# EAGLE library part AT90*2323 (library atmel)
MICROCONTROLLER 2 Kbytes FLASH 128 bytes SRAM 128 bytes EEPROM

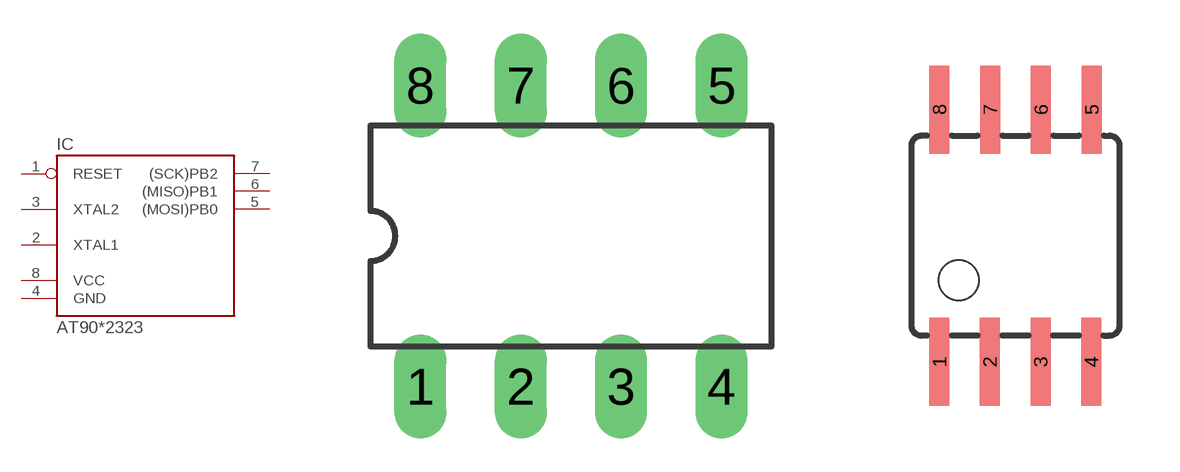
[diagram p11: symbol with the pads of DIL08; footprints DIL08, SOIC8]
Designator prefix IC

## AT90LS2323P (OC_FARNELL: unknown; OC_NEWARK: unknown), AT90S2323P (OC_FARNELL: unknown; OC_NEWARK: unknown)  [DIL08]
1  RESET  in
2  XTAL1
3  XTAL2
4  GND  pwr
5  (MOSI)PB0
6  (MISO)PB1
7  (SCK)PB2
8  VCC  pwr

## AT90LS2323S (OC_FARNELL: unknown; OC_NEWARK: unknown), AT90S2323S (OC_FARNELL: unknown; OC_NEWARK: unknown)  [SOIC8]
Pads as for DIL08

## Footprint DIL08 (pad centres in mm)
Dual In Line
drill 0.813 long: 1 -3.81,-3.81; 2 -1.27,-3.81; 3 1.27,-3.81; 4 3.81,-3.81; 5 3.81,3.81; 6 1.27,3.81; 7 -1.27,3.81; 8 -3.81,3.81

## Footprint SOIC8 (pad centres in mm)
Wide Plastic Gull Wing Small Outline Package
smd 0.5 x 2.2: 1 -1.905,-3.154; 2 -0.645,-3.154; 3 0.625,-3.154; 4 1.895,-3.154; 5 1.905,3.154; 6 0.635,3.154; 7 -0.635,3.154; 8 -1.905,3.154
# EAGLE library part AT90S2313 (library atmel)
MICROCONTROLLER 2 Kbytes FLASH 128 bytes SRAM 128 bytes EEPROM UART

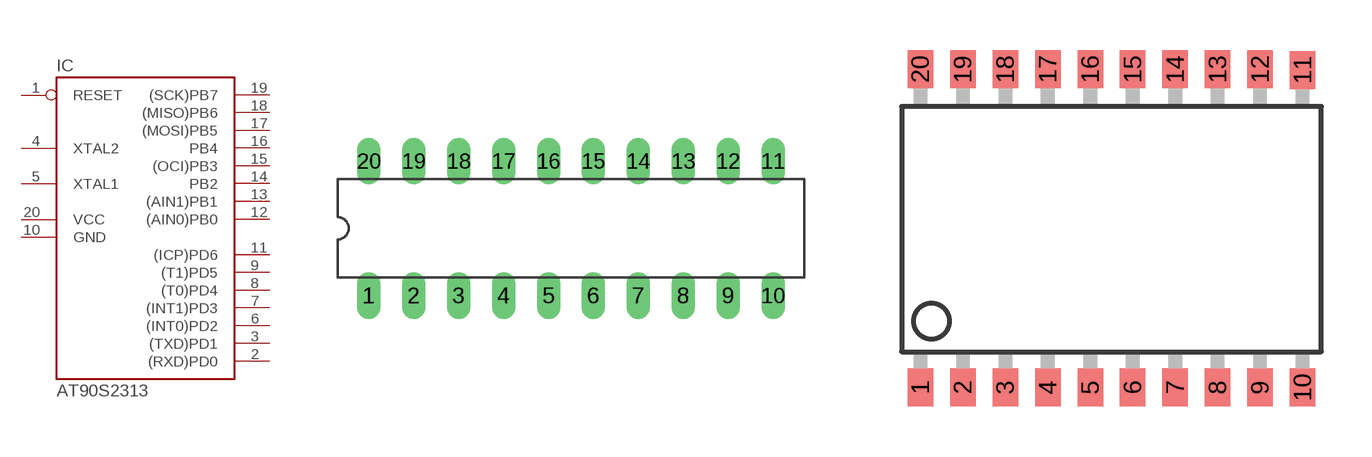
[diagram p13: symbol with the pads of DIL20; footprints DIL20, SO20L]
Designator prefix IC

## AT90S2313P (OC_FARNELL: unknown; OC_NEWARK: unknown)  [DIL20]
1  RESET
2  (RXD)PD0
3  (TXD)PD1
4  XTAL2
5  XTAL1
6  (INT0)PD2
7  (INT1)PD3
8  (T0)PD4
9  (T1)PD5
10  GND  pwr
11  (ICP)PD6
12  (AIN0)PB0
13  (AIN1)PB1
14  PB2
15  (OCI)PB3
16  PB4
17  (MOSI)PB5
18  (MISO)PB6
19  (SCK)PB7
20  VCC  pwr

## AT90S2313S (OC_FARNELL: unknown; OC_NEWARK: unknown)  [SO20L]
Pads as for DIL20

## Footprint DIL20 (pad centres in mm)
Dual In Line
drill 0.813 long: 1 -11.43,-3.81; 2 -8.89,-3.81; 3 -6.35,-3.81; 4 -3.81,-3.81; 5 -1.27,-3.81; 6 1.27,-3.81; 7 3.81,-3.81; 8 6.35,-3.81; 9 8.89,-3.81; 10 11.43,-3.81; 11 11.43,3.81; 12 8.89,3.81; 13 6.35,3.81; 14 3.81,3.81; 15 1.27,3.81; 16 -1.27,3.81; 17 -3.81,3.81; 18 -6.35,3.81; 19 -8.89,3.81; 20 -11.43,3.81

## Footprint SO20L (pad centres in mm)
Small Outline Package SOIC 0.300"
smd 0.762 x 1.143: 1 -5.08,-5.131; 2 -3.81,-5.131; 3 -2.54,-5.131; 4 -1.27,-5.131; 5 0,-5.131; 6 1.27,-5.131; 7 2.54,-5.131; 8 3.81,-5.131; 9 5.08,-5.131; 10 6.35,-5.131; 11 6.35,4.369; 12 5.08,4.394; 13 3.81,4.394; 14 2.54,4.394; 15 1.27,4.394; 16 0,4.394; 17 -1.27,4.394; 18 -2.54,4.394; 19 -3.81,4.394; 20 -5.08,4.394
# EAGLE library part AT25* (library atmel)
SPI bus serial EEPROM

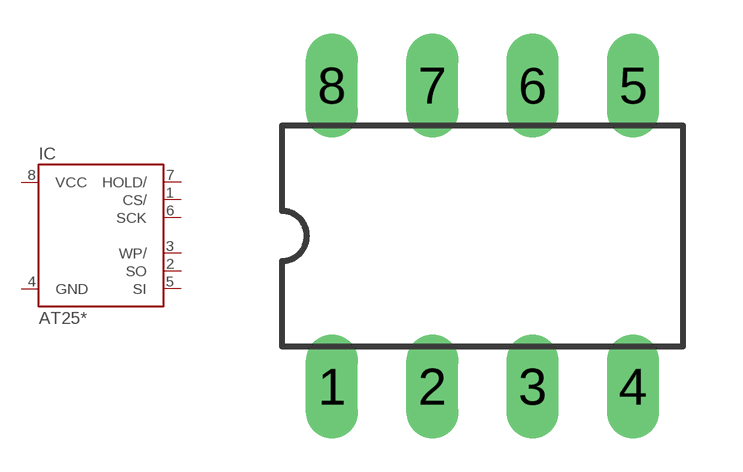
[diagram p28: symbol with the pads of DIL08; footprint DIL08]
Designator prefix IC

## AT25P (MPN: CAT25040LI-G; OC_FARNELL: 1718045; OC_NEWARK: 06R0588)  [DIL08]
1  CS/  in
2  SO  in
3  WP/  in
4  GND  pwr
5  SI
6  SCK
7  HOLD/  in
8  VCC  pwr

## Footprint DIL08 (pad centres in mm)
Dual In Line
drill 0.813 long: 1 -3.81,-3.81; 2 -1.27,-3.81; 3 1.27,-3.81; 4 3.81,-3.81; 5 3.81,3.81; 6 1.27,3.81; 7 -1.27,3.81; 8 -3.81,3.81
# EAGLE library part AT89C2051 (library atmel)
80C31 MICROCONTROLLER 2 Kbytes FLASH 2.7 V

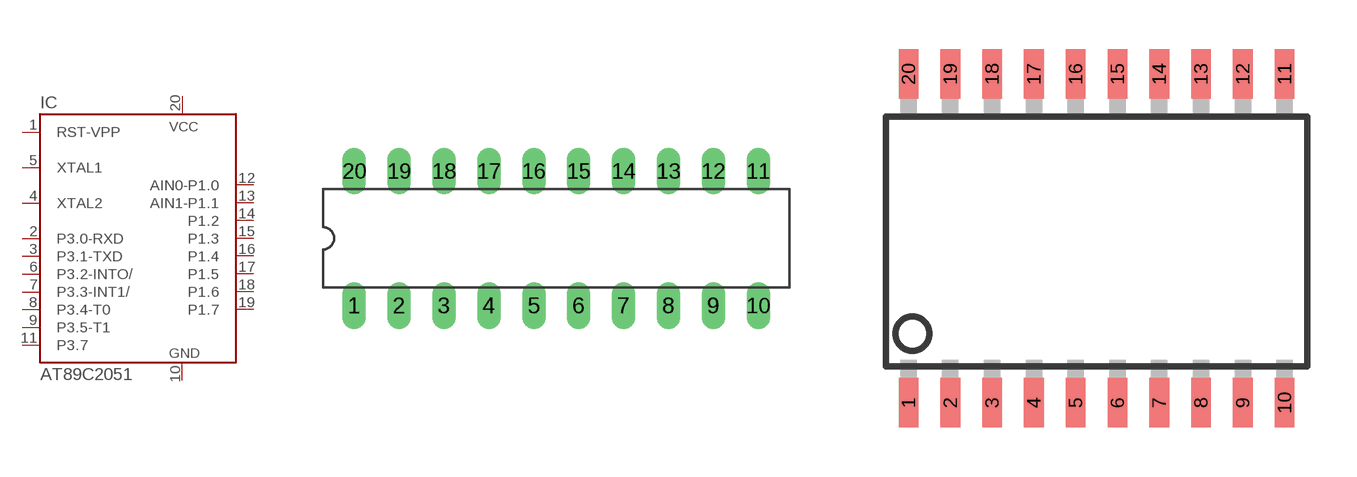
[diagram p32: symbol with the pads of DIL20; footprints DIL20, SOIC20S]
Designator prefix IC

## AT89C2051P (MPN: AT89C2051-12PU; OC_FARNELL: 1699389; OC_NEWARK: 80P3687)  [DIL20]
1  RST-VPP  in
2  P3.0-RXD
3  P3.1-TXD
4  XTAL2  out
5  XTAL1  in
6  P3.2-INTO/
7  P3.3-INT1/
8  P3.4-T0
9  P3.5-T1
10  GND  pwr
11  P3.7
12  AIN0-P1.0
13  AIN1-P1.1
14  P1.2
15  P1.3
16  P1.4
17  P1.5
18  P1.6
19  P1.7
20  VCC  pwr

## AT89C2051S (MPN: AT89C2051-12SU; OC_FARNELL: 1699390; OC_NEWARK: 80P3688)  [SOIC20S]
Pads as for DIL20

## Footprint DIL20 (pad centres in mm)
Dual In Line
drill 0.813 long: 1 -11.43,-3.81; 2 -8.89,-3.81; 3 -6.35,-3.81; 4 -3.81,-3.81; 5 -1.27,-3.81; 6 1.27,-3.81; 7 3.81,-3.81; 8 6.35,-3.81; 9 8.89,-3.81; 10 11.43,-3.81; 11 11.43,3.81; 12 8.89,3.81; 13 6.35,3.81; 14 3.81,3.81; 15 1.27,3.81; 16 -1.27,3.81; 17 -3.81,3.81; 18 -6.35,3.81; 19 -8.89,3.81; 20 -11.43,3.81

## Footprint SOIC20S (pad centres in mm)
Wide Plastic Gull Wing Small Outline Package
smd 0.6 x 1.5: 1 -5.715,-5; 2 -4.445,-5; 3 -3.175,-5; 4 -1.905,-5; 5 -0.635,-5; 6 0.635,-5; 7 1.905,-5; 8 3.175,-5; 9 4.445,-5; 10 5.715,-5; 11 5.715,5; 12 4.445,5; 13 3.175,5; 14 1.905,5; 15 0.635,5; 16 -0.635,5; 17 -1.905,5; 18 -3.175,5; 19 -4.445,5; 20 -5.715,5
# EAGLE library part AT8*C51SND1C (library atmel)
Single-Chip Flash Microcontroller with MP3 Decoder and Human Interface Source: www.atmel.com .. doc4109.pdf

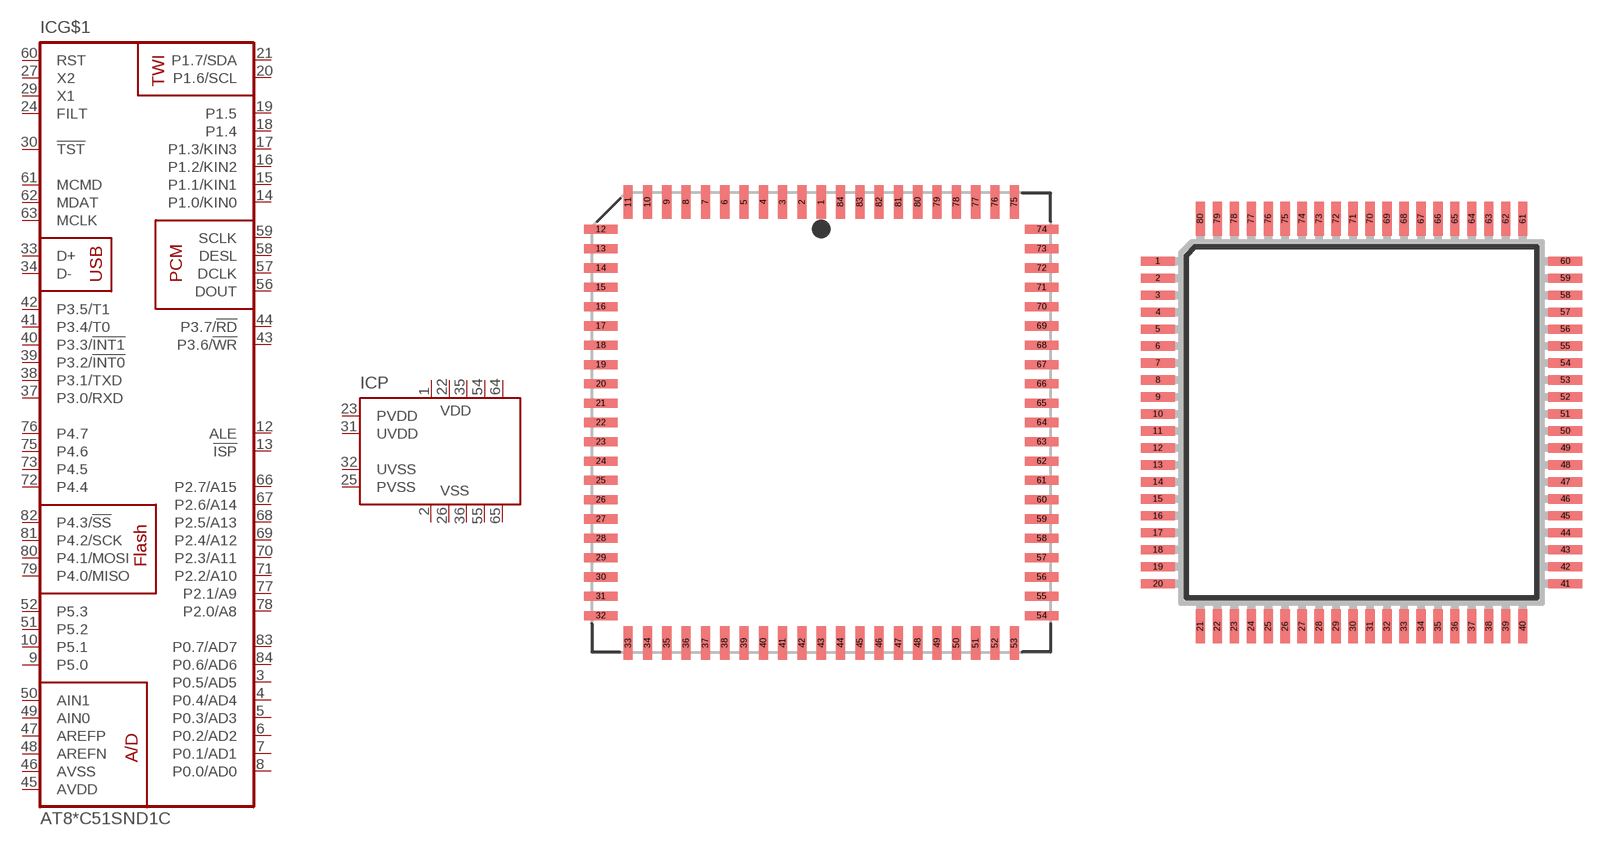
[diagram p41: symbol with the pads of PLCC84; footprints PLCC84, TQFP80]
Designator prefix IC; gates G$1=AT89C51SND1C P=P-AT89C51SND1C

## AT80C51SND1C (OC_FARNELL: unknown; OC_NEWARK: unknown), AT89C51SND1C (OC_FARNELL: 1095728; OC_NEWARK: unknown)  [PLCC84]
1  P:VDD  pwr
2  P:VSS  pwr
3  G$1:P0.5/AD5
4  G$1:P0.4/AD4
5  G$1:P0.3/AD3
6  G$1:P0.2/AD2
7  G$1:P0.1/AD1
8  G$1:P0.0/AD0
9  G$1:P5.0
10  G$1:P5.1
12  G$1:ALE  out
13  G$1:!ISP  in
14  G$1:P1.0/KIN0
15  G$1:P1.1/KIN1
16  G$1:P1.2/KIN2
17  G$1:P1.3/KIN3
18  G$1:P1.4
19  G$1:P1.5
20  G$1:P1.6/SCL
21  G$1:P1.7/SDA
22  P:VDD  pwr
23  P:PVDD  pwr
24  G$1:FILT  in
25  P:PVSS  pwr
26  P:VSS  pwr
27  G$1:X2  out
29  G$1:X1  in
30  G$1:!TST  in
31  P:UVDD  pwr
32  P:UVSS  pwr
33  G$1:D+
34  G$1:D-
35  P:VDD  pwr
36  P:VSS  pwr
37  G$1:P3.0/RXD
38  G$1:P3.1/TXD
39  G$1:P3.2/!INT0
40  G$1:P3.3/!INT1
41  G$1:P3.4/T0
42  G$1:P3.5/T1
43  G$1:P3.6/!WR
44  G$1:P3.7/!RD
45  G$1:AVDD  pwr
46  G$1:AVSS  pwr
47  G$1:AREFP  in
48  G$1:AREFN  in
49  G$1:AIN0  in
50  G$1:AIN1  in
51  G$1:P5.2
52  G$1:P5.3
54  P:VDD  pwr
55  P:VSS  pwr
56  G$1:DOUT  out
57  G$1:DCLK  out
58  G$1:DESL  out
59  G$1:SCLK  out
60  G$1:RST  in
61  G$1:MCMD
62  G$1:MDAT
63  G$1:MCLK  out
64  P:VDD  pwr
65  P:VSS  pwr
66  G$1:P2.7/A15
67  G$1:P2.6/A14
68  G$1:P2.5/A13
69  G$1:P2.4/A12
70  G$1:P2.3/A11
71  G$1:P2.2/A10
72  G$1:P4.4  in
73  G$1:P4.5  in
75  G$1:P4.6  in
76  G$1:P4.7  in
77  G$1:P2.1/A9
78  G$1:P2.0/A8
79  G$1:P4.0/MISO  in
80  G$1:P4.1/MOSI  out
81  G$1:P4.2/SCK  out
82  G$1:P4.3/!SS  in
83  G$1:P0.7/AD7
84  G$1:P0.6/AD6

## AT80C51SND1C-RO (OC_FARNELL: unknown; OC_NEWARK: unknown), AT89C51SND1C-RO (OC_FARNELL: 1095728; OC_NEWARK: unknown)  [TQFP80]
1  G$1:ALE  out
2  G$1:!ISP  in
3  G$1:P1.0/KIN0
4  G$1:P1.1/KIN1
5  G$1:P1.2/KIN2
6  G$1:P1.3/KIN3
7  G$1:P1.4
8  G$1:P1.5
9  G$1:P1.6/SCL
10  G$1:P1.7/SDA
11  P:VDD  pwr
12  P:VDD  pwr
13  G$1:FILT  in
14  P:PVSS  pwr
15  P:VSS  pwr
16  G$1:X2  out
17  G$1:X1  in
18  G$1:!TST  in
19  P:UVDD  pwr
20  P:UVSS  pwr
21  G$1:D+
22  G$1:D-
23  P:VDD  pwr
24  P:VSS  pwr
25  G$1:P3.0/RXD
26  G$1:P3.1/TXD
27  G$1:P3.2/!INT0
28  G$1:P3.3/!INT1
29  G$1:P3.4/T0
30  G$1:P3.5/T1
31  G$1:P3.6/!WR
32  G$1:P3.7/!RD
33  G$1:AVDD  pwr
34  G$1:AVSS  pwr
35  G$1:AREFP  in
36  G$1:AREFN  in
37  G$1:AIN0  in
38  G$1:AIN1  in
39  G$1:P5.2
40  G$1:P5.3
41  P:VDD  pwr
42  P:VSS  pwr
43  G$1:DOUT  out
44  G$1:DCLK  out
45  G$1:DESL  out
46  G$1:SCLK  out
47  G$1:RST  in
48  G$1:MCMD
49  G$1:MDAT
50  G$1:MCLK  out
51  P:PVDD  pwr
52  P:VSS  pwr
53  G$1:P2.7/A15
54  G$1:P2.6/A14
55  G$1:P2.5/A13
56  G$1:P2.4/A12
57  G$1:P2.3/A11
58  G$1:P2.2/A10
59  G$1:P4.4  in
60  G$1:P4.5  in
61  G$1:P4.6  in
62  G$1:P4.7  in
63  G$1:P2.1/A9
64  G$1:P2.0/A8
65  G$1:P4.0/MISO  in
66  G$1:P4.1/MOSI  out
67  G$1:P4.2/SCK  out
68  G$1:P4.3/!SS  in
69  G$1:P0.7/AD7
70  G$1:P0.6/AD6
71  P:VDD  pwr
72  P:VSS  pwr
73  G$1:P0.5/AD5
74  G$1:P0.4/AD4
75  G$1:P0.3/AD3
76  G$1:P0.2/AD2
77  G$1:P0.1/AD1
78  G$1:P0.0/AD0
79  G$1:P5.0
80  G$1:P5.1

## AT80C51SND1C-7H (OC_FARNELL: unknown; OC_NEWARK: unknown), AT89C51SND1C-7H (OC_FARNELL: unknown; OC_NEWARK: unknown)  [BGA81]
A1  G$1:ALE  out
A2  G$1:P5.0
A3  G$1:P0.3/AD3
A4  G$1:P0.2/AD2
A5  P:VDD  pwr
A6  G$1:P4.2/SCK  out
A7  G$1:P4.0/MISO  in
A8  G$1:P2.0/A8
A9  G$1:P4.6  in
B1  G$1:P1.1/KIN1
B2  G$1:!ISP  in
B3  G$1:P0.0/AD0
B4  G$1:P0.4/AD4
B5  G$1:P0.1/AD1
B6  G$1:P4.3/!SS  in
B7  G$1:P4.1/MOSI  out
B8  G$1:P4.7  in
B9  G$1:P4.4  in
C1  G$1:P1.2/KIN2
C2  G$1:P1.3/KIN3
C3  G$1:P1.0/KIN0
C4  G$1:P5.1
C5  P:VSS  pwr
C6  G$1:P0.6/AD6
C7  G$1:P2.1/A9
C8  G$1:P2.2/A10
C9  G$1:P2.5/A13
D1  G$1:P1.4
D2  G$1:P1.5
D3  G$1:P1.7/SDA
D4  G$1:P1.6/SCL
D5  G$1:P0.5/AD5
D6  G$1:P0.7/AD7
D7  G$1:P4.5  in
D8  G$1:P2.6/A14
D9  G$1:P2.4/A12
E1  P:VDD  pwr
E2  G$1:X1  in
E3  P:PVDD  pwr
E4  G$1:FILT  in
E6  G$1:P2.7/A15
E7  P:VSS  pwr
E8  G$1:P2.3/A11
E9  P:VDD  pwr
F1  G$1:X2  out
F2  P:PVSS  pwr
F3  P:UVSS  pwr
F4  G$1:P3.4/T0
F5  G$1:AVDD  pwr
F6  G$1:MDAT
F7  G$1:MCLK  out
F8  G$1:MCMD
F9  G$1:RST  in
G1  P:VSS  pwr
G2  G$1:!TST  in
G3  P:VDD  pwr
G4  G$1:P3.5/T1
G5  G$1:P3.7/!RD
G6  G$1:P5.3
G7  G$1:DOUT  out
G8  G$1:SCLK  out
G9  G$1:DESL  out
H1  P:UVDD  pwr
H2  G$1:D-
H3  G$1:P3.1/TXD
H4  G$1:P3.3/!INT1
H5  G$1:AIN0  in
H6  G$1:AVSS  pwr
H7  G$1:AIN1  in
H8  P:VSS  pwr
H9  G$1:DCLK  out
J1  G$1:D+
J2  P:VSS  pwr
J3  G$1:P3.0/RXD
J4  G$1:P3.2/!INT0
J5  G$1:P3.6/!WR
J6  G$1:AREFN  in
J7  G$1:AREFP  in
J8  G$1:P5.2
J9  P:VDD  pwr

## Footprint PLCC84 (pad centres in mm)
Plastic J-Lead Chip Carrier
smd 0.6 x 2.2: 1 0,14.5; 2 -1.27,14.5; 3 -2.54,14.5; 4 -3.81,14.5; 5 -5.08,14.5; 6 -6.35,14.5; 7 -7.62,14.5; 8 -8.89,14.5; 9 -10.16,14.5; 10 -11.43,14.5; 11 -12.7,14.5; 33 -12.7,-14.5; 34 -11.43,-14.5; 35 -10.16,-14.5; 36 -8.89,-14.5; 37 -7.62,-14.5; 38 -6.35,-14.5; 39 -5.08,-14.5; 40 -3.81,-14.5; 41 -2.54,-14.5; 42 -1.27,-14.5; 43 0,-14.5; 44 1.27,-14.5; 45 2.54,-14.5; 46 3.81,-14.5; 47 5.08,-14.5; 48 6.35,-14.5; 49 7.62,-14.5; 50 8.89,-14.5; 51 10.16,-14.5; 52 11.43,-14.5; 53 12.7,-14.5; 75 12.7,14.5; 76 11.43,14.5; 77 10.16,14.5; 78 8.89,14.5; 79 7.62,14.5; 80 6.35,14.5; 81 5.08,14.5; 82 3.81,14.5; 83 2.54,14.5; 84 1.27,14.5
smd 2.2 x 0.6: 12 -14.5,12.7; 13 -14.5,11.43; 14 -14.5,10.16; 15 -14.5,8.89; 16 -14.5,7.62; 17 -14.5,6.35; 18 -14.5,5.08; 19 -14.5,3.81; 20 -14.5,2.54; 21 -14.5,1.27; 22 -14.5,0; 23 -14.5,-1.27; 24 -14.5,-2.54; 25 -14.5,-3.81; 26 -14.5,-5.08; 27 -14.5,-6.35; 28 -14.5,-7.62; 29 -14.5,-8.89; 30 -14.5,-10.16; 31 -14.5,-11.43; 32 -14.5,-12.7; 54 14.5,-12.7; 55 14.5,-11.43; 56 14.5,-10.16; 57 14.5,-8.89; 58 14.5,-7.62; 59 14.5,-6.35; 60 14.5,-5.08; 61 14.5,-3.81; 62 14.5,-2.54; 63 14.5,-1.27; 64 14.5,0; 65 14.5,1.27; 66 14.5,2.54; 67 14.5,3.81; 68 14.5,5.08; 69 14.5,6.35; 70 14.5,7.62; 71 14.5,8.89; 72 14.5,10.16; 73 14.5,11.43; 74 14.5,12.7

## Footprint TQFP80 (pad centres in mm)
TQFP 80 thin quad flat pack Source: www.atmwel.com .. doc4109.pdf
smd 1.3 x 0.35: 1 -7.8,6.175; 2 -7.8,5.525; 3 -7.8,4.875; 4 -7.8,4.225; 5 -7.8,3.575; 6 -7.8,2.925; 7 -7.8,2.275; 8 -7.8,1.625; 9 -7.8,0.975; 10 -7.8,0.325; 11 -7.8,-0.325; 12 -7.8,-0.975; 13 -7.8,-1.625; 14 -7.8,-2.275; 15 -7.8,-2.925; 16 -7.8,-3.575; 17 -7.8,-4.225; 18 -7.8,-4.875; 19 -7.8,-5.525; 20 -7.8,-6.175; 41 7.8,-6.175; 42 7.8,-5.525; 43 7.8,-4.875; 44 7.8,-4.225; 45 7.8,-3.575; 46 7.8,-2.925; 47 7.8,-2.275; 48 7.8,-1.625; 49 7.8,-0.975; 50 7.8,-0.325; 51 7.8,0.325; 52 7.8,0.975; 53 7.8,1.625; 54 7.8,2.275; 55 7.8,2.925; 56 7.8,3.575; 57 7.8,4.225; 58 7.8,4.875; 59 7.8,5.525; 60 7.8,6.175
smd 0.35 x 1.3: 21 -6.175,-7.8; 22 -5.525,-7.8; 23 -4.875,-7.8; 24 -4.225,-7.8; 25 -3.575,-7.8; 26 -2.925,-7.8; 27 -2.275,-7.8; 28 -1.625,-7.8; 29 -0.975,-7.8; 30 -0.325,-7.8; 31 0.325,-7.8; 32 0.975,-7.8; 33 1.625,-7.8; 34 2.275,-7.8; 35 2.925,-7.8; 36 3.575,-7.8; 37 4.225,-7.8; 38 4.875,-7.8; 39 5.525,-7.8; 40 6.175,-7.8; 61 6.175,7.8; 62 5.525,7.8; 63 4.875,7.8; 64 4.225,7.8; 65 3.575,7.8; 66 2.925,7.8; 67 2.275,7.8; 68 1.625,7.8; 69 0.975,7.8; 70 0.325,7.8; 71 -0.325,7.8; 72 -0.975,7.8; 73 -1.625,7.8; 74 -2.275,7.8; 75 -2.925,7.8; 76 -3.575,7.8; 77 -4.225,7.8; 78 -4.875,7.8; 79 -5.525,7.8; 80 -6.175,7.8

## Footprint BGA81 (pad centres in mm)
Ball Grid Array 81 leads Source: www.atmwel.com .. doc4109.pdf
smd 0.46 x 0.46: A1 -3.2,3.2; A2 -2.4,3.2; A3 -1.6,3.2; A4 -0.8,3.2; A5 0,3.2; A6 0.8,3.2; A7 1.6,3.2; A8 2.4,3.2; A9 3.2,3.2; B1 -3.2,2.4; B2 -2.4,2.4; B3 -1.6,2.4; B4 -0.8,2.4; B5 0,2.4; B6 0.8,2.4; B7 1.6,2.4; B8 2.4,2.4; B9 3.2,2.4; C1 -3.2,1.6; C2 -2.4,1.6; C3 -1.6,1.6; C4 -0.8,1.6; C5 0,1.6; C6 0.8,1.6; C7 1.6,1.6; C8 2.4,1.6; C9 3.2,1.6; D1 -3.2,0.8; D2 -2.4,0.8; D3 -1.6,0.8; D4 -0.8,0.8; D5 0,0.8; D6 0.8,0.8; D7 1.6,0.8; D8 2.4,0.8; D9 3.2,0.8; E1 -3.2,0; E2 -2.4,0; E3 -1.6,0; E4 -0.8,0; E5 0,0; E6 0.8,0; E7 1.6,0; E8 2.4,0; E9 3.2,0; F1 -3.2,-0.8; F2 -2.4,-0.8; F3 -1.6,-0.8; F4 -0.8,-0.8; F5 0,-0.8; F6 0.8,-0.8; F7 1.6,-0.8; F8 2.4,-0.8; F9 3.2,-0.8; G1 -3.2,-1.6; G2 -2.4,-1.6; G3 -1.6,-1.6; G4 -0.8,-1.6; G5 0,-1.6; G6 0.8,-1.6; G7 1.6,-1.6; G8 2.4,-1.6; G9 3.2,-1.6; H1 -3.2,-2.4; H2 -2.4,-2.4; H3 -1.6,-2.4; H4 -0.8,-2.4; H5 0,-2.4; H6 0.8,-2.4; H7 1.6,-2.4; H8 2.4,-2.4; H9 3.2,-2.4; J1 -3.2,-3.2; J2 -2.4,-3.2; J3 -1.6,-3.2; J4 -0.8,-3.2; J5 0,-3.2; J6 0.8,-3.2; J7 1.6,-3.2; J8 2.4,-3.2; J9 3.2,-3.2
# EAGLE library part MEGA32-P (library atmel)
MICROCONTROLLER 32 Kbytes FLASH 2 Kbytes SRAM 1 Kbytes EEPROM USART 8-channel 10 bit ADC Source: www.atmel.com .. doc2503.pdf

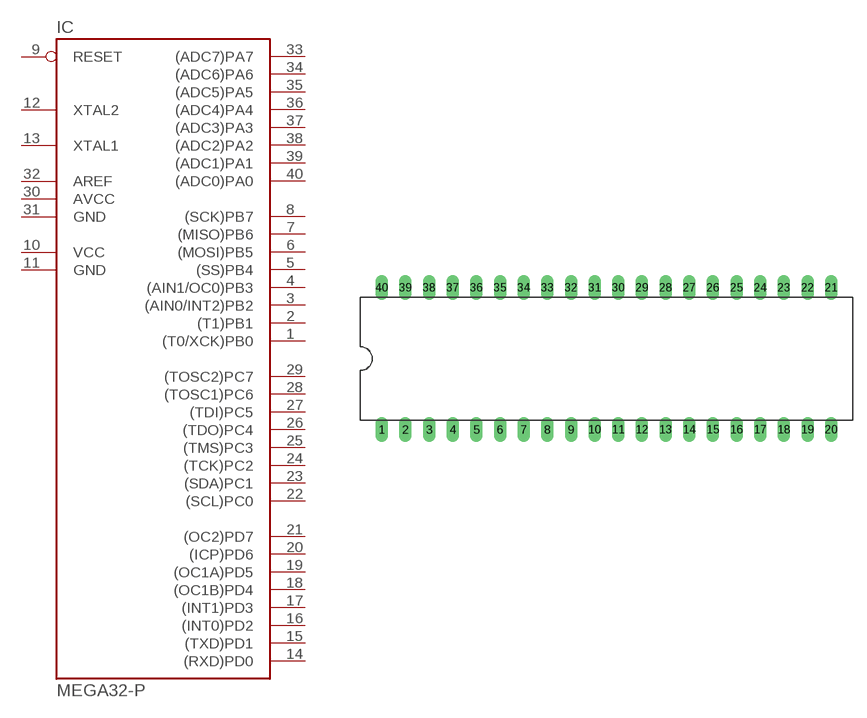
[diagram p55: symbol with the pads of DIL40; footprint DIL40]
Designator prefix IC

## MEGA32-P (MPN: ATMEGA32-16PU; OC_FARNELL: 1661729; OC_NEWARK: 51P1794)  [DIL40]
1  (T0/XCK)PB0
2  (T1)PB1
3  (AIN0/INT2)PB2
4  (AIN1/OC0)PB3
5  (SS)PB4
6  (MOSI)PB5
7  (MISO)PB6
8  (SCK)PB7
9  RESET  in
10  VCC  pwr
11  GND  pwr
12  XTAL2
13  XTAL1
14  (RXD)PD0
15  (TXD)PD1
16  (INT0)PD2
17  (INT1)PD3
18  (OC1B)PD4
19  (OC1A)PD5
20  (ICP)PD6
21  (OC2)PD7
22  (SCL)PC0
23  (SDA)PC1
24  (TCK)PC2
25  (TMS)PC3
26  (TDO)PC4
27  (TDI)PC5
28  (TOSC1)PC6
29  (TOSC2)PC7
30  AVCC  pwr
31  GND  pwr
32  AREF  pas
33  (ADC7)PA7
34  (ADC6)PA6
35  (ADC5)PA5
36  (ADC4)PA4
37  (ADC3)PA3
38  (ADC2)PA2
39  (ADC1)PA1
40  (ADC0)PA0

## Footprint DIL40 (pad centres in mm)
Dual In Line
drill 0.813 long: 1 -24.13,-7.62; 2 -21.59,-7.62; 3 -19.05,-7.62; 4 -16.51,-7.62; 5 -13.97,-7.62; 6 -11.43,-7.62; 7 -8.89,-7.62; 8 -6.35,-7.62; 9 -3.81,-7.62; 10 -1.27,-7.62; 11 1.27,-7.62; 12 3.81,-7.62; 13 6.35,-7.62; 14 8.89,-7.62; 15 11.43,-7.62; 16 13.97,-7.62; 17 16.51,-7.62; 18 19.05,-7.62; 19 21.59,-7.62; 20 24.13,-7.62; 21 24.13,7.62; 22 21.59,7.62; 23 19.05,7.62; 24 16.51,7.62; 25 13.97,7.62; 26 11.43,7.62; 27 8.89,7.62; 28 6.35,7.62; 29 3.81,7.62; 30 1.27,7.62; 31 -1.27,7.62; 32 -3.81,7.62; 33 -6.35,7.62; 34 -8.89,7.62; 35 -11.43,7.62; 36 -13.97,7.62; 37 -16.51,7.62; 38 -19.05,7.62; 39 -21.59,7.62; 40 -24.13,7.62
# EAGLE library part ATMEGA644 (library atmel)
8-bit Microcontroller with 64K Bytes In-System Programmable Flash Source: http://www.atmel.com/dyn/resources/prod_documents/doc2593.pdf

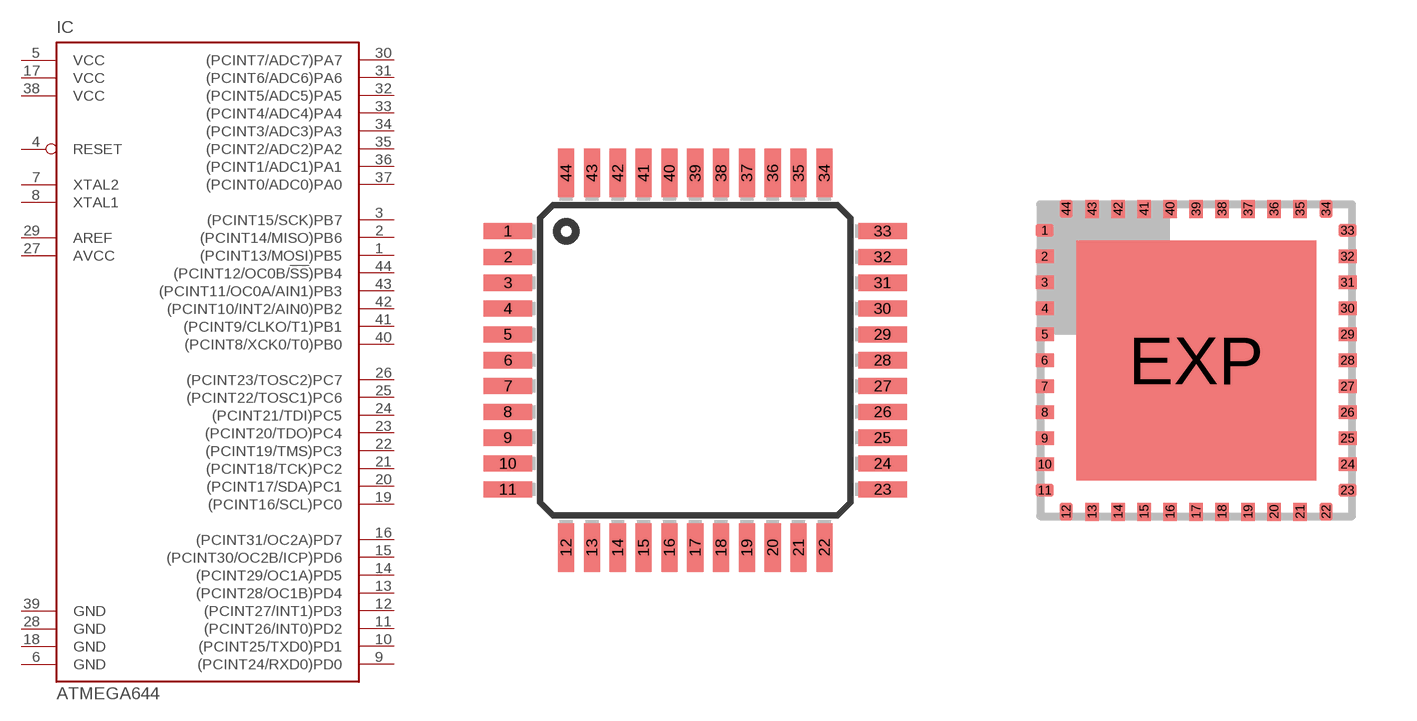
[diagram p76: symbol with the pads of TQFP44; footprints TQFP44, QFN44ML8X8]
Designator prefix IC

## ATMEGA644A (MPN: ATMEGA644PV-10AU; OC_FARNELL: 1455123; OC_NEWARK: 58M3748)  [TQFP44]
1  (PCINT13/MOSI)PB5
2  (PCINT14/MISO)PB6
3  (PCINT15/SCK)PB7
4  RESET  in
5  VCC  pwr
6  GND  pwr
7  XTAL2
8  XTAL1
9  (PCINT24/RXD0)PD0
10  (PCINT25/TXD0)PD1
11  (PCINT26/INT0)PD2
12  (PCINT27/INT1)PD3
13  (PCINT28/OC1B)PD4
14  (PCINT29/OC1A)PD5
15  (PCINT30/OC2B/ICP)PD6
16  (PCINT31/OC2A)PD7
17  VCC  pwr
18  GND  pwr
19  (PCINT16/SCL)PC0  out
20  (PCINT17/SDA)PC1  out
21  (PCINT18/TCK)PC2  out
22  (PCINT19/TMS)PC3  out
23  (PCINT20/TDO)PC4  out
24  (PCINT21/TDI)PC5  out
25  (PCINT22/TOSC1)PC6  out
26  (PCINT23/TOSC2)PC7  out
27  AVCC  pwr
28  GND  pwr
29  AREF  pas
30  (PCINT7/ADC7)PA7
31  (PCINT6/ADC6)PA6
32  (PCINT5/ADC5)PA5
33  (PCINT4/ADC4)PA4
34  (PCINT3/ADC3)PA3
35  (PCINT2/ADC2)PA2
36  (PCINT1/ADC1)PA1
37  (PCINT0/ADC0)PA0
38  VCC  pwr
39  GND  pwr
40  (PCINT8/XCK0/T0)PB0
41  (PCINT9/CLKO/T1)PB1
42  (PCINT10/INT2/AIN0)PB2
43  (PCINT11/OC0A/AIN1)PB3
44  (PCINT12/OC0B/!SS!)PB4

## ATMEGA644M (MPN: ATMEGA644PV-10MU; OC_FARNELL: 1748529; OC_NEWARK: 26R5637)  [QFN44ML8X8]
Pads as for TQFP44

## Footprint TQFP44 (pad centres in mm)
44-lead Thin Quad Flat Package
smd 1.5 x 0.5: 1 -5.8,4; 2 -5.8,3.2; 3 -5.8,2.4; 4 -5.8,1.6; 5 -5.8,0.8; 6 -5.8,0; 7 -5.8,-0.8; 8 -5.8,-1.6; 9 -5.8,-2.4; 10 -5.8,-3.2; 11 -5.8,-4; 23 5.8,-4; 24 5.8,-3.2; 25 5.8,-2.4; 26 5.8,-1.6; 27 5.8,-0.8; 28 5.8,0; 29 5.8,0.8; 30 5.8,1.6; 31 5.8,2.4; 32 5.8,3.2; 33 5.8,4
smd 0.5 x 1.5: 12 -4,-5.8; 13 -3.2,-5.8; 14 -2.4,-5.8; 15 -1.6,-5.8; 16 -0.8,-5.8; 17 0,-5.8; 18 0.8,-5.8; 19 1.6,-5.8; 20 2.4,-5.8; 21 3.2,-5.8; 22 4,-5.8; 34 4,5.8; 35 3.2,5.8; 36 2.4,5.8; 37 1.6,5.8; 38 0.8,5.8; 39 0,5.8; 40 -0.8,5.8; 41 -1.6,5.8; 42 -2.4,5.8; 43 -3.2,5.8; 44 -4,5.8

## Footprint QFN44ML8X8 (pad centres in mm)
44-Lead Plastic Quad Flat No Lead Package (ML) 8x8 mm Body (QFN) Source: http://ww1.microchip.com/downloads/en/devicedoc/39632c.pdf
smd 0.45 x 0.33: 1 -3.788,3.25; 2 -3.788,2.6; 3 -3.788,1.95; 4 -3.788,1.3; 5 -3.788,0.65; 6 -3.788,0; 7 -3.788,-0.65; 8 -3.788,-1.3; 9 -3.788,-1.95; 10 -3.788,-2.6; 11 -3.788,-3.25; 23 3.788,-3.25; 24 3.788,-2.6; 25 3.788,-1.95; 26 3.788,-1.3; 27 3.788,-0.65; 28 3.788,0; 29 3.788,0.65; 30 3.788,1.3; 31 3.788,1.95; 32 3.788,2.6; 33 3.788,3.25
smd 0.33 x 0.45: 12 -3.25,-3.788; 13 -2.6,-3.788; 14 -1.95,-3.788; 15 -1.3,-3.788; 16 -0.65,-3.788; 17 0,-3.788; 18 0.65,-3.788; 19 1.3,-3.788; 20 1.95,-3.788; 21 2.6,-3.788; 22 3.25,-3.788; 34 3.25,3.788; 35 2.6,3.788; 36 1.95,3.788; 37 1.3,3.788; 38 0.65,3.788; 39 0,3.788; 40 -0.65,3.788; 41 -1.3,3.788; 42 -1.95,3.788; 43 -2.6,3.788; 44 -3.25,3.788
smd 6 x 6: EXP 0,0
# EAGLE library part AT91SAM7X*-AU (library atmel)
Highly integrated Flash microcontrollers based on the 32-bit ARM RISC processor 512/256/128 Kbyte high-speed Flash and 128/64/32 Kbyte SRAM, a large set of peripherals, including an 802.3 Ethernet MAC and a CAN controller Source: http://www.atmel.com/dyn/resources/prod_documents/6120s.pdf

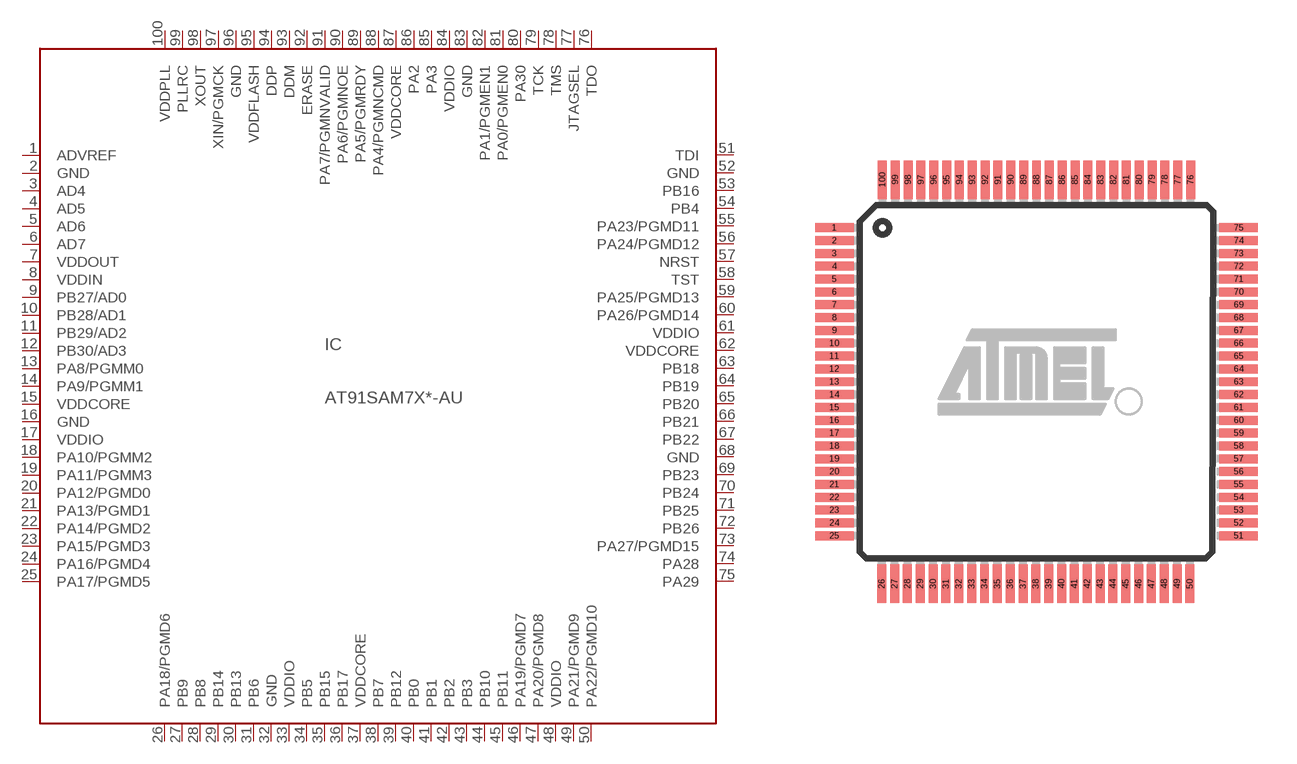
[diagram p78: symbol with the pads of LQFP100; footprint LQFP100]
Designator prefix IC

## AT91SAM7X128-AU (MPN: AT91SAM7X128B-AU; OC_FARNELL: 1288326; OC_NEWARK: 26R5682), AT91SAM7X256-AU (MPN: AT91SAM7X256B-AU; OC_FARNELL: 1288327; OC_NEWARK: 26R5683), AT91SAM7X512-AU (MPN: AT91SAM7X512-AU; OC_FARNELL: 1288328; OC_NEWARK: 23M5090)  [LQFP100]
1  ADVREF
2  GND
3  AD4
4  AD5
5  AD6
6  AD7
7  VDDOUT
8  VDDIN
9  PB27/AD0
10  PB28/AD1
11  PB29/AD2
12  PB30/AD3
13  PA8/PGMM0
14  PA9/PGMM1
15  VDDCORE
16  GND
17  VDDIO
18  PA10/PGMM2
19  PA11/PGMM3
20  PA12/PGMD0
21  PA13/PGMD1
22  PA14/PGMD2
23  PA15/PGMD3
24  PA16/PGMD4
25  PA17/PGMD5
26  PA18/PGMD6
27  PB9
28  PB8
29  PB14
30  PB13
31  PB6
32  GND
33  VDDIO
34  PB5
35  PB15
36  PB17
37  VDDCORE
38  PB7
39  PB12
40  PB0
41  PB1
42  PB2
43  PB3
44  PB10
45  PB11
46  PA19/PGMD7
47  PA20/PGMD8
48  VDDIO
49  PA21/PGMD9
50  PA22/PGMD10
51  TDI
52  GND
53  PB16
54  PB4
55  PA23/PGMD11
56  PA24/PGMD12
57  NRST
58  TST
59  PA25/PGMD13
60  PA26/PGMD14
61  VDDIO
62  VDDCORE
63  PB18
64  PB19
65  PB20
66  PB21
67  PB22
68  GND
69  PB23
70  PB24
71  PB25
72  PB26
73  PA27/PGMD15
74  PA28
75  PA29
76  TDO
77  JTAGSEL
78  TMS
79  TCK
80  PA30
81  PA0/PGMEN0
82  PA1/PGMEN1
83  GND
84  VDDIO
85  PA3
86  PA2
87  VDDCORE
88  PA4/PGMNCMD
89  PA5/PGMRDY
90  PA6/PGMNOE
91  PA7/PGMNVALID
92  ERASE
93  DDM
94  DDP
95  VDDFLASH
96  GND
97  XIN/PGMCK
98  XOUT
99  PLLRC
100  VDDPLL

## Footprint LQFP100 (pad centres in mm)
LQFP 100 Source: 6120s.pdf
smd 1.5 x 0.35: 1 -7.875,6; 2 -7.875,5.5; 3 -7.875,5; 4 -7.875,4.5; 5 -7.875,4; 6 -7.875,3.5; 7 -7.875,3; 8 -7.875,2.5; 9 -7.875,2; 10 -7.875,1.5; 11 -7.875,1; 12 -7.875,0.5; 13 -7.875,0; 14 -7.875,-0.5; 15 -7.875,-1; 16 -7.875,-1.5; 17 -7.875,-2; 18 -7.875,-2.5; 19 -7.875,-3; 20 -7.875,-3.5; 21 -7.875,-4; 22 -7.875,-4.5; 23 -7.875,-5; 24 -7.875,-5.5; 25 -7.875,-6; 51 7.875,-6; 52 7.875,-5.5; 53 7.875,-5; 54 7.875,-4.5; 55 7.875,-4; 56 7.875,-3.5; 57 7.875,-3; 58 7.875,-2.5; 59 7.875,-2; 60 7.875,-1.5; 61 7.875,-1; 62 7.875,-0.5; 63 7.875,0; 64 7.875,0.5; 65 7.875,1; 66 7.875,1.5; 67 7.875,2; 68 7.875,2.5; 69 7.875,3; 70 7.875,3.5; 71 7.875,4; 72 7.875,4.5; 73 7.875,5; 74 7.875,5.5; 75 7.875,6
smd 0.35 x 1.5: 26 -6.025,-7.875; 27 -5.525,-7.875; 28 -5.025,-7.875; 29 -4.525,-7.875; 30 -4.025,-7.875; 31 -3.525,-7.875; 32 -3.025,-7.875; 33 -2.525,-7.875; 34 -2.025,-7.875; 35 -1.525,-7.875; 36 -1.025,-7.875; 37 -0.525,-7.875; 38 -0.025,-7.875; 39 0.475,-7.875; 40 0.975,-7.875; 41 1.475,-7.875; 42 1.975,-7.875; 43 2.475,-7.875; 44 2.975,-7.875; 45 3.475,-7.875; 46 3.975,-7.875; 47 4.475,-7.875; 48 4.975,-7.875; 49 5.475,-7.875; 50 5.975,-7.875; 76 6,7.875; 77 5.5,7.875; 78 5,7.875; 79 4.5,7.875; 80 4,7.875; 81 3.5,7.875; 82 3,7.875; 83 2.5,7.875; 84 2,7.875; 85 1.5,7.875; 86 1,7.875; 87 0.5,7.875; 88 0,7.875; 89 -0.5,7.875; 90 -1,7.875; 91 -1.5,7.875; 92 -2,7.875; 93 -2.5,7.875; 94 -3,7.875; 95 -3.5,7.875; 96 -4,7.875; 97 -4.5,7.875; 98 -5,7.875; 99 -5.5,7.875; 100 -6,7.875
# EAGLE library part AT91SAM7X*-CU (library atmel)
Highly integrated Flash microcontrollers based on the 32-bit ARM RISC processor 512/256/128 Kbyte high-speed Flash and 128/64/32 Kbyte SRAM, a large set of peripherals, including an 802.3 Ethernet MAC and a CAN controller Source: http://www.atmel.com/dyn/resources/prod_documents/6120s.pdf

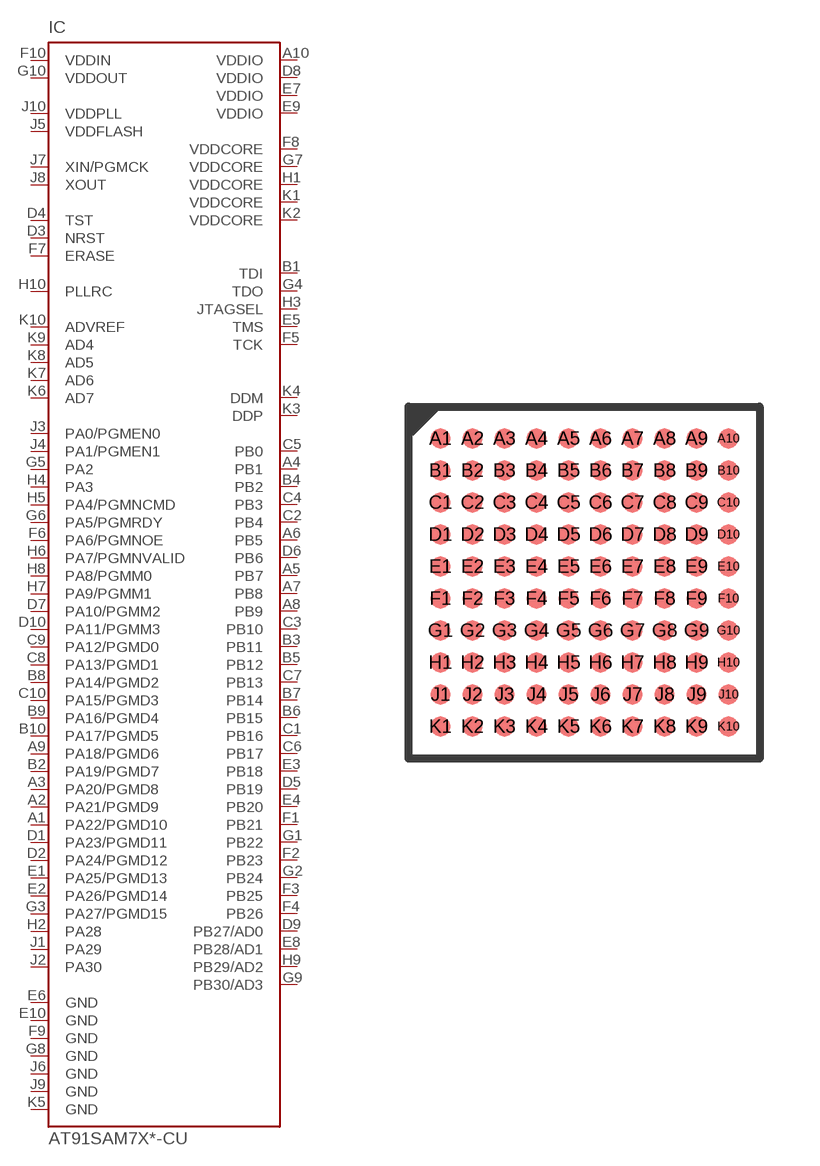
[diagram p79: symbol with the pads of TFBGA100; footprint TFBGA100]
Designator prefix IC

## AT91SAM7X128-CU (OC_FARNELL: unknown; OC_NEWARK: unknown), AT91SAM7X256-CU (OC_FARNELL: unknown; OC_NEWARK: unknown), AT91SAM7X512-CU (OC_FARNELL: unknown; OC_NEWARK: unknown)  [TFBGA100]
A1  PA22/PGMD10
A2  PA21/PGMD9
A3  PA20/PGMD8
A4  PB1
A5  PB7
A6  PB5
A7  PB8
A8  PB9
A9  PA18/PGMD6
A10  VDDIO
B1  TDI
B2  PA19/PGMD7
B3  PB11
B4  PB2
B5  PB12
B6  PB15
B7  PB14
B8  PA14/PGMD2
B9  PA16/PGMD4
B10  PA17/PGMD5
C1  PB16
C2  PB4
C3  PB10
C4  PB3
C5  PB0
C6  PB17
C7  PB13
C8  PA13/PGMD1
C9  PA12/PGMD0
C10  PA15/PGMD3
D1  PA23/PGMD11
D2  PA24/PGMD12
D3  NRST
D4  TST
D5  PB19
D6  PB6
D7  PA10/PGMM2
D8  VDDIO
D9  PB27/AD0
D10  PA11/PGMM3
E1  PA25/PGMD13
E2  PA26/PGMD14
E3  PB18
E4  PB20
E5  TMS
E6  GND
E7  VDDIO
E8  PB28/AD1
E9  VDDIO
E10  GND
F1  PB21
F2  PB23
F3  PB25
F4  PB26
F5  TCK
F6  PA6/PGMNOE
F7  ERASE
F8  VDDCORE
F9  GND
F10  VDDIN
G1  PB22
G2  PB24
G3  PA27/PGMD15
G4  TDO
G5  PA2
G6  PA5/PGMRDY
G7  VDDCORE
G8  GND
G9  PB30/AD3
G10  VDDOUT  out
H1  VDDCORE
H2  PA28
H3  JTAGSEL
H4  PA3
H5  PA4/PGMNCMD
H6  PA7/PGMNVALID
H7  PA9/PGMM1
H8  PA8/PGMM0
H9  PB29/AD2
H10  PLLRC
J1  PA29
J2  PA30
J3  PA0/PGMEN0
J4  PA1/PGMEN1
J5  VDDFLASH
J6  GND
J7  XIN/PGMCK
J8  XOUT  out
J9  GND
J10  VDDPLL
K1  VDDCORE
K2  VDDCORE
K3  DDP
K4  DDM
K5  GND
K6  AD7
K7  AD6
K8  AD5
K9  AD4
K10  ADVREF

## Footprint TFBGA100 (pad centres in mm)
TFBGA 100 Source: 6120s.pdf
smd 0.5 x 0.5: A1 -3.6,3.6; A2 -2.8,3.6; A3 -2,3.6; A4 -1.2,3.6; A5 -0.4,3.6; A6 0.4,3.6; A7 1.2,3.6; A8 2,3.6; A9 2.8,3.6; A10 3.6,3.6; B1 -3.6,2.8; B2 -2.8,2.8; B3 -2,2.8; B4 -1.2,2.8; B5 -0.4,2.8; B6 0.4,2.8; B7 1.2,2.8; B8 2,2.8; B9 2.8,2.8; B10 3.6,2.8; C1 -3.6,2; C2 -2.8,2; C3 -2,2; C4 -1.2,2; C5 -0.4,2; C6 0.4,2; C7 1.2,2; C8 2,2; C9 2.8,2; C10 3.6,2; D1 -3.6,1.2; D2 -2.8,1.2; D3 -2,1.2; D4 -1.2,1.2; D5 -0.4,1.2; D6 0.4,1.2; D7 1.2,1.2; D8 2,1.2; D9 2.8,1.2; D10 3.6,1.2; E1 -3.6,0.4; E2 -2.8,0.4; E3 -2,0.4; E4 -1.2,0.4; E5 -0.4,0.4; E6 0.4,0.4; E7 1.2,0.4; E8 2,0.4; E9 2.8,0.4; E10 3.6,0.4; F1 -3.6,-0.4; F2 -2.8,-0.4; F3 -2,-0.4; F4 -1.2,-0.4; F5 -0.4,-0.4; F6 0.4,-0.4; F7 1.2,-0.4; F8 2,-0.4; F9 2.8,-0.4; F10 3.6,-0.4; G1 -3.6,-1.2; G2 -2.8,-1.2; G3 -2,-1.2; G4 -1.2,-1.2; G5 -0.4,-1.2; G6 0.4,-1.2; G7 1.2,-1.2; G8 2,-1.2; G9 2.8,-1.2; G10 3.6,-1.2; H1 -3.6,-2; H2 -2.8,-2; H3 -2,-2; H4 -1.2,-2; H5 -0.4,-2; H6 0.4,-2; H7 1.2,-2; H8 2,-2; H9 2.8,-2; H10 3.6,-2; J1 -3.6,-2.8; J2 -2.8,-2.8; J3 -2,-2.8; J4 -1.2,-2.8; J5 -0.4,-2.8; J6 0.4,-2.8; J7 1.2,-2.8; J8 2,-2.8; J9 2.8,-2.8; J10 3.6,-2.8; K1 -3.6,-3.6; K2 -2.8,-3.6; K3 -2,-3.6; K4 -1.2,-3.6; K5 -0.4,-3.6; K6 0.4,-3.6; K7 1.2,-3.6; K8 2,-3.6; K9 2.8,-3.6; K10 3.6,-3.6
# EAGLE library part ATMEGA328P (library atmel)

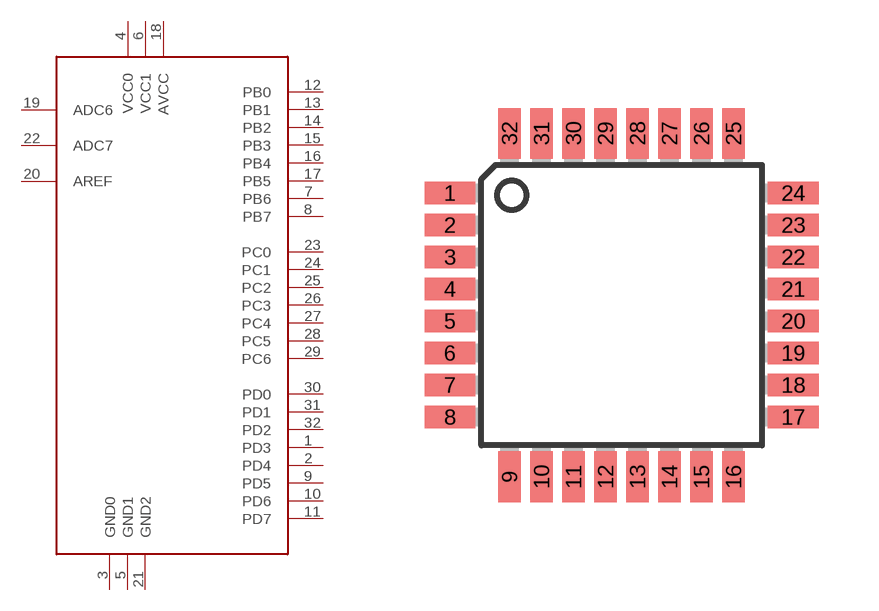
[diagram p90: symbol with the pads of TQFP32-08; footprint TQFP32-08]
Designator prefix -

## ATMEGA328P  [TQFP32-08]
1  PD3
2  PD4
3  GND0
4  VCC0
5  GND1
6  VCC1
7  PB6
8  PB7
9  PD5
10  PD6
11  PD7
12  PB0
13  PB1
14  PB2
15  PB3
16  PB4
17  PB5
18  AVCC
19  ADC6
20  AREF
21  GND2
22  ADC7
23  PC0
24  PC1
25  PC2
26  PC3
27  PC4
28  PC5
29  PC6
30  PD0
31  PD1
32  PD2

## Footprint TQFP32-08 (pad centres in mm)
Thin Plasic Quad Flat Package Grid 0.8 mm
smd 1.27 x 0.559: 1 -4.293,2.8; 2 -4.293,2; 3 -4.293,1.2; 4 -4.293,0.4; 5 -4.293,-0.4; 6 -4.293,-1.2; 7 -4.293,-2; 8 -4.293,-2.8; 17 4.293,-2.8; 18 4.293,-2; 19 4.293,-1.2; 20 4.293,-0.4; 21 4.293,0.4; 22 4.293,1.2; 23 4.293,2; 24 4.293,2.8
smd 0.559 x 1.27: 9 -2.8,-4.293; 10 -2,-4.293; 11 -1.2,-4.293; 12 -0.4,-4.293; 13 0.4,-4.293; 14 1.2,-4.293; 15 2,-4.293; 16 2.8,-4.293; 25 2.8,4.293; 26 2,4.293; 27 1.2,4.293; 28 0.4,4.293; 29 -0.4,4.293; 30 -1.2,4.293; 31 -2,4.293; 32 -2.8,4.293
